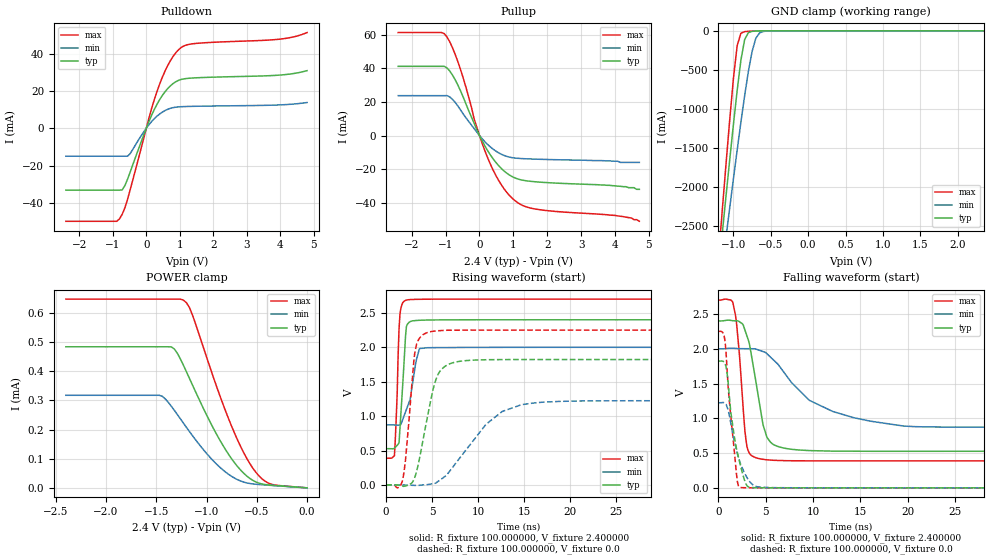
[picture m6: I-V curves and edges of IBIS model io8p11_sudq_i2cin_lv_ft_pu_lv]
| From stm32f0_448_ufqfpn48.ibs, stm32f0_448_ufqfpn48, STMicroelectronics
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|   Model io8p11_sudq_i2cin_lv_ft_pu_lv
[Model]  io8p11_sudq_i2cin_lv_ft_pu_lv
Model_type I/O
Polarity   Non-Inverting
Enable   Active-Low
Vinl =   0.720000V
Vinh =   1.680000V
Vmeas =  1.200000V
Cref =   50.000000pF
Rref =   100.000000M
Vref =   0.0V
C_comp   2.067900pF   1.988600pF   2.164800pF
[Temperature Range]   25.000000   0.125000k   -40.000000
[Pullup Reference]   2.400000V   2.000000V   2.700000V
[Pulldown Reference]   0.0V   0.0V   0.0V
[POWER Clamp Reference]   2.400000V   2.000000V   2.700000V
[GND Clamp Reference]   0.0V   0.0V   0.0V
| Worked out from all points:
|   slope of the pulldown table from 0 to 0.36 V, typ, clamps not added: 25.5 ohm
|   slope of the pullup table from 0 to 0.36 V, typ, clamps not added: 28.4 ohm
|   GND clamp passes 1 mA (typ) near -0.64 V on its own axis
|   rising waveform, R_fixture 100.000000, V_fixture 2.400000: 20-80 % time 509ps typ, 1.01ns min, 338ps max; typ from 0.527 V to 2.4 V
|   rising waveform, R_fixture 100.000000, V_fixture 0.0: 20-80 % time 1.65ns typ, 4.61ns min, 851ps max; typ from 0.001 V to 1.82 V
|   falling waveform, R_fixture 100.000000, V_fixture 2.400000: 20-80 % time 1.39ns typ, 5.8ns min, 779ps max; typ from 2.4 V to 0.527 V
|   falling waveform, R_fixture 100.000000, V_fixture 0.0: 20-80 % time 1.18ns typ, 1.41ns min, 862ps max; typ from 1.82 V to 0.001 V
[Pulldown]
|Voltage   I(typ)   I(min)   I(max)
-2.4V     -33.16mA   -14.98mA   -49.86mA
-880mV    -33.16mA   -14.98mA   -49.86mA
-800mV    -33.16mA   -14.98mA   -48.55mA
-640mV    -30.75mA   -14.98mA   -42.77mA
-480mV    -23.43mA   -13.57mA   -32.92mA
80mV      3.651mA    1.905mA    5.506mA
400mV     15.37mA    7.665mA    23.73mA
720mV     22.75mA    10.69mA    36.23mA
1.04V     26.18mA    11.57mA    43.27mA
1.52V     27.09mA    11.81mA    45.55mA
4V        28.55mA    12.55mA    47.81mA
4.8V      30.9mA     13.81mA    51.31mA
[Pullup]
|Voltage   I(typ)   I(min)   I(max)
-2.4V     41.12mA    23.71mA    61.2mA
-1.12V    41.12mA    23.71mA    61.2mA
-960mV    40.18mA    23.71mA    58.57mA
-800mV    36.02mA    21.56mA    52.31mA
-560mV    26.55mA    15.19mA    39.22mA
-160mV    7.425mA    4.163mA    10.02mA
240mV     -8.976mA   -5.327mA   -13.21mA
640mV     -19.5mA    -11.08mA   -29.16mA
1.04V     -25.15mA   -13.38mA   -38.61mA
1.68V     -27.56mA   -14.07mA   -43.81mA
4V        -29.9mA    -15.3mA    -47.5mA
4.72V     -32mA      -16mA      -51mA
[GND_clamp]
|Voltage   I(typ)   I(min)   I(max)
-2.4V     -9.567A    -9.921A    -9.731A
-1.2V     -3.09A     -3.428A    -2.911A
-1.15V    -2.606A    -3.04A     -2.31A
-1.1V     -2.127A    -2.655A    -1.719A
-1.05V    -1.657A    -2.274A    -1.146A
-950mV    -765.3mA   -1.53A     -190.2mA
-900mV    -376.6mA   -1.172A    -30.81mA
-850mV    -112.3mA   -832.5mA   -10.23mA
-750mV    -6.57mA    -264.6mA   -4.026mA
-700mV    -2.581mA   -94.26mA   -2.329mA
-600mV    -416.4uA   -8.158mA   -368uA
2.35V     0A         0A         0A
[POWER_clamp]
|Voltage   I(typ)   I(min)   I(max)
-2.4V     483.6uA    317.3uA    647uA
-1.47V    483.6uA    317.3uA    647uA
-1.32V    475.8uA    265.5uA    647uA
-1.23V    420.2uA    221.8uA    643.4uA
-1.17V    375.2uA    193uA      618uA
-1.14V    352.5uA    178.9uA    592.4uA
-840mV    147.3uA    62.31uA    290.1uA
-690mV    72.45uA    27.82uA    163.1uA
-540mV    25.82uA    13.54uA    67.87uA
-450mV    13.39uA    10.73uA    31.49uA
-360mV    9.214uA    8.518uA    13uA
0V        0A         0A         0A
[Ramp]
| variable   typ   min   max
dV/dt_r  1.09263/1.64817n   0.73353/4.60984n   1.34926/0.84996n
dV/dt_f  1.12407/1.39503n   0.67652/5.79419n   1.38686/0.78752n
R_load = 100.000000
[Rising Waveform]
R_fixture= 100.000000
V_fixture= 2.400000
V_fixture_min= 2.000000
V_fixture_max= 2.700000
|time   V(typ)   V(min)   V(max)
0s        526.5mV    872.5mV    388.6mV
900.9ps   534.2mV    870.9mV    424.8mV
1.201ns   576.8mV    869.7mV    1.339V
1.401ns   612.7mV    869.2mV    2.271V
1.602ns   1.037V     879.1mV    2.568V
2.202ns   2.302V     1.096V     2.686V
2.603ns   2.373V     1.241V     2.693V
3.203ns   2.389V     1.764V     2.696V
3.704ns   2.393V     1.984V     2.698V
49.85ns   2.4V       2V         2.7V
[Rising Waveform]
R_fixture= 100.000000
V_fixture= 0.0
V_fixture_min= 0.0
V_fixture_max= 0.0
|time   V(typ)   V(min)   V(max)
0s        1.021mV    1.338mV    909.3uV
1.802ns   -18.02mV   115.5uV    72.01mV
2.102ns   -14.38mV   -1.442mV   363.8mV
3.103ns   107.3mV    -6.785mV   1.91V
4.505ns   1V         4.872mV    2.215V
5.405ns   1.53V      28.7mV     2.238V
6.507ns   1.733V     134.3mV    2.247V
10.91ns   1.819V     887.2mV    2.25V
14.71ns   1.822V     1.166V     2.249V
49.85ns   1.822V     1.224V     2.25V
[Falling Waveform]
R_fixture= 100.000000
V_fixture= 2.400000
V_fixture_min= 2.000000
V_fixture_max= 2.700000
|time   V(typ)   V(min)   V(max)
0s        2.4V       2V         2.7V
1.502ns   2.403V     2.008V     2.672V
1.902ns   2.401V     2.004V     2.374V
3.003ns   2.184V     2.001V     597.8mV
4.004ns   1.485V     1.993V     432.2mV
5.105ns   733.1mV    1.93V      404.1mV
7.407ns   561mV      1.571V     390.8mV
12.01ns   529.1mV    1.103V     388.5mV
19.52ns   526.5mV    890mV      388.6mV
49.85ns   526.5mV    872.5mV    388.6mV
[Falling Waveform]
R_fixture= 100.000000
V_fixture= 0.0
V_fixture_min= 0.0
V_fixture_max= 0.0
|time   V(typ)   V(min)   V(max)
0s        1.822V     1.224V     2.25V
500.5ps   1.82V      1.229V     2.223V
700.7ps   1.784V     1.216V     2.103V
1.101ns   1.389V     1.073V     1.318V
1.301ns   1.09V      929mV      1.028V
1.902ns   564.8mV    545.2mV    196.9mV
2.302ns   329.9mV    355.5mV    6.272mV
3.003ns   33.37mV    150.8mV    2.422mV
4.605ns   2.375mV    9.903mV    1.335mV
49.85ns   1.021mV    1.338mV    909.3uV
